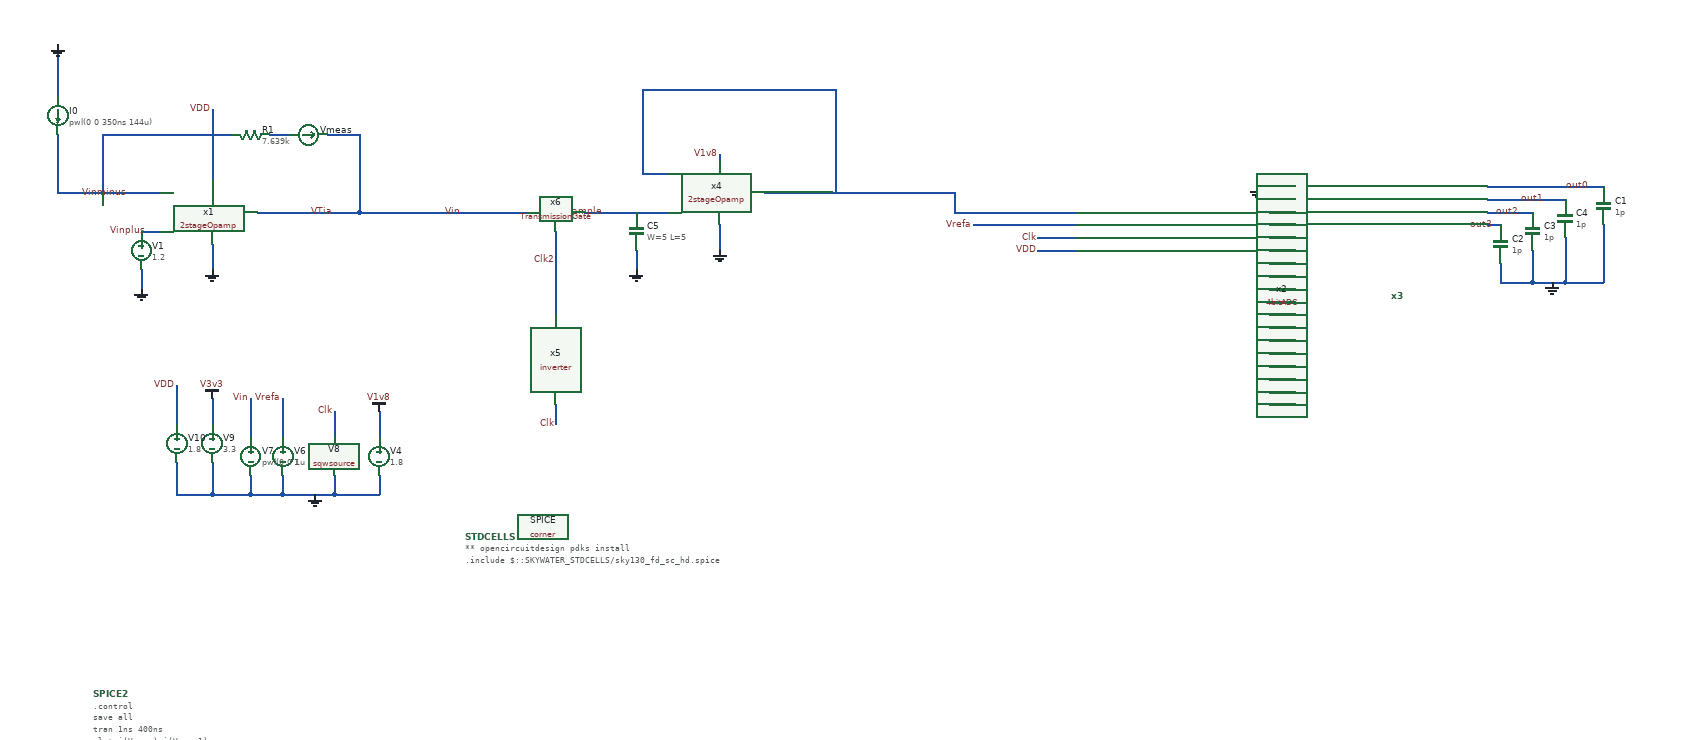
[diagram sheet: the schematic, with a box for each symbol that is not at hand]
v {xschem version=3.4.4 file_version=1.2
}
G {}
K {}
V {}
S {}
E {}
B 2 420 -600 1220 -200 {flags=graph
y1=0
y2=2
ypos1=0.1
ypos2=2.1
divy=1.8
subdivy=1
unity=1
x1=1.93715e-07
x2=4.23938e-07
divx=5
subdivx=1
xlabmag=1.0
ylabmag=1.0
node=BUS_NAME,x3.xoutput19.a_109_47#,x3.xoutput18.a_109_47#,x3.xoutput17.a_109_47#,x3.xoutput16.a_109_47#
color=4
dataset=-1
unitx=1
logx=0
logy=0
digital=1}
N -755 -80 -755 10 {
lab=Vinminus}
N -755 10 -595 10 {
lab=Vinminus}
N -755 -220 -755 -140 {
lab=GND}
N -445 40 -285 40 {
lab=VTia}
N -285 -80 -285 40 {
lab=VTia}
N -685 -80 -485 -80 {
lab=Vinminus}
N -685 -80 -685 10 {
lab=Vinminus}
N -625 130 -625 160 {
lab=GND}
N -425 -80 -395 -80 {
lab=#net1}
N -335 -80 -285 -80 {
lab=VTia}
N -285 40 -195 40 {
lab=VTia}
N 770 100 830 100 {
lab=VDD}
N 770 80 830 80 {
lab=Clk}
N 770 60 830 60 {
lab=Vrefa}
N 1130 40 1170 40 {
lab=#net2}
N 1130 60 1170 60 {
lab=#net3}
N 1130 80 1170 80 {
lab=#net4}
N 1130 100 1170 100 {
lab=#net5}
N 1130 120 1170 120 {
lab=#net6}
N 1130 140 1170 140 {
lab=#net7}
N 1130 160 1170 160 {
lab=#net8}
N 1130 180 1170 180 {
lab=#net9}
N 1130 200 1170 200 {
lab=#net10}
N 1130 220 1170 220 {
lab=#net11}
N 1130 240 1170 240 {
lab=#net12}
N 1130 260 1170 260 {
lab=#net13}
N 1130 280 1170 280 {
lab=#net14}
N 1130 300 1170 300 {
lab=#net15}
N 1130 320 1170 320 {
lab=#net16}
N 1130 340 1170 340 {
lab=#net17}
N 1470 0 1650 0 {
lab=out0}
N 1470 20 1590 20 {
lab=out1}
N 1470 40 1540 40 {
lab=out2}
N 1470 60 1490 60 {
lab=out3}
N 1490 120 1490 150 {
lab=GND}
N 1540 100 1540 150 {
lab=GND}
N 1590 80 1590 150 {
lab=GND}
N 1650 60 1650 150 {
lab=GND}
N 1590 150 1650 150 {
lab=GND}
N 1540 150 1590 150 {
lab=GND}
N 1490 150 1540 150 {
lab=GND}
N 1110 0 1170 0 {
lab=GND}
N 1150 20 1170 20 {
lab=VDD}
N 640 40 830 40 {
lab=#net18}
N 670 60 770 60 {
lab=Vrefa}
N -195 40 -125 40 {
lab=VTia}
N -515 -30 -515 -10 {
lab=VDD}
N -515 90 -515 110 {
lab=GND}
N 640 10 640 40 {
lab=#net18}
N 450 10 640 10 {
lab=#net18}
N -625 70 -595 70 {
lab=Vinplus}
N -515 -120 -515 -30 {
lab=VDD}
N -515 110 -515 130 {
lab=GND}
N -125 40 -25 40 {
lab=VTia}
N 145 100 145 130 {
lab=GND}
N 145 40 195 40 {
lab=Vsample}
N 365 10 455 10 {
lab=#net18}
N 455 -150 455 10 {
lab=#net18}
N 155 -150 455 -150 {
lab=#net18}
N 275 60 275 100 {
lab=GND}
N 155 -20 195 -20 {
lab=#net18}
N 155 -150 155 -20 {
lab=#net18}
N 345 10 365 10 {
lab=#net18}
N 275 -50 275 -40 {
lab=V1v8}
N 20 340 20 370 {
lab=Clk}
N 20 70 20 110 {
lab=Clk2}
N 20 110 20 130 {
lab=Clk2}
N 20 130 20 200 {
lab=Clk2}
N 65 40 95 40 {
lab=Vsample}
N 95 40 145 40 {
lab=Vsample}
N -405 330 -405 390 {
lab=Vrefa}
N -455 330 -455 390 {
lab=Vin}
N -255 350 -255 390 {
lab=V1v8}
N -325 350 -325 390 {
lab=Clk}
N -455 450 -455 480 {
lab=GND}
N -325 480 -255 480 {
lab=GND}
N -255 450 -255 480 {
lab=GND}
N -405 450 -405 480 {
lab=GND}
N -325 450 -325 480 {
lab=GND}
N -455 480 -405 480 {
lab=GND}
N -405 480 -325 480 {
lab=GND}
N -515 330 -515 370 {
lab=V3v3}
N -515 430 -515 460 {
lab=GND}
N -515 460 -515 480 {
lab=GND}
N -515 480 -455 480 {
lab=GND}
N -570 310 -570 370 {
lab=VDD}
N -570 430 -570 460 {
lab=GND}
N -570 460 -570 480 {
lab=GND}
N -570 480 -520 480 {
lab=GND}
N -520 480 -515 480 {
lab=GND}
C {devices/isource.sym} -755 -110 0 0 {name=I0 value="pwl(0 0 350ns 144u)"}
C {devices/gnd.sym} -755 -220 2 0 {name=l1 lab=GND}
C {devices/res.sym} -455 -80 1 0 {name=R1
value=7.639k
footprint=1206
device=resistor
m=1}
C {devices/lab_pin.sym} -325 40 1 0 {name=p1 sig_type=std_logic lab=VTia}
C {devices/lab_pin.sym} -645 10 1 0 {name=p2 sig_type=std_logic lab=Vinminus}
C {devices/vsource.sym} -625 100 0 0 {name=V1 value=1.2 savecurrent=false}
C {devices/gnd.sym} -625 160 0 0 {name=l2 lab=GND}
C {devices/ammeter.sym} -365 -80 3 0 {name=Vmeas savecurrent=true}
C {sky130_fd_pr/corner.sym} 0 530 0 0 {name=SPICE only_toplevel=true corner=tt}
C {devices/launcher.sym} -870 570 0 0 {name=h15
descr="Annotate OP" 
tclcommand="set show_hidden_texts 1; xschem annotate_op"
}
C {devices/launcher.sym} -860 620 0 0 {name=h3
descr="Netlist & sim" 
tclcommand="xschem netlist; xschem simulate"}
C {devices/code_shown.sym} -700 790 0 0 {name=SPICE2
only_toplevel=false 
value="
.control
save all

tran 1ns 400ns
plot i(Vmeas) i(Vmeas1)
plot Vtia Vmeas
plot Vinadc Vtia
plot Clk
plot Vtia Clk
plot out0 out1 out2 out3
plot Vinminus Vinplus
appendwrite
write Tia_ADCtb.raw
.endc
"}
C {devices/lab_pin.sym} 770 80 0 0 {name=p10 lab=Clk}
C {devices/lab_pin.sym} 1150 20 2 1 {name=p11 sig_type=std_logic lab=VDD}
C {devices/code.sym} -120 545 0 0 {name=STDCELLS
only_toplevel=true
format="tcleval( @value )"
value="
** opencircuitdesign pdks install
.include $::SKYWATER_STDCELLS/sky130_fd_sc_hd.spice

"
spice_ignore=false}
C {devices/lab_pin.sym} 770 100 2 1 {name=p12 sig_type=std_logic lab=VDD}
C {devices/gnd.sym} 1110 0 1 0 {name=l4 lab=GND}
C {devices/capa.sym} 1650 30 0 0 {name=C1
m=1
value=1p
footprint=1206
device="ceramic capacitor"}
C {devices/capa.sym} 1490 90 0 0 {name=C2
m=1
value=1p
footprint=1206
device="ceramic capacitor"}
C {devices/capa.sym} 1540 70 0 0 {name=C3
m=1
value=1p
footprint=1206
device="ceramic capacitor"}
C {devices/capa.sym} 1590 50 0 0 {name=C4
m=1
value=1p
footprint=1206
device="ceramic capacitor"}
C {devices/gnd.sym} 1570 150 0 0 {name=l5 lab=GND}
C {devices/lab_pin.sym} 1630 0 1 0 {name=p13 sig_type=std_logic lab=out0}
C {devices/lab_pin.sym} 1560 20 1 0 {name=p14 sig_type=std_logic lab=out1}
C {devices/lab_pin.sym} 1520 40 1 0 {name=p15 sig_type=std_logic lab=out2}
C {devices/lab_pin.sym} 1480 60 1 0 {name=p16 sig_type=std_logic lab=out3}
C {devices/lab_pin.sym} 670 60 0 0 {name=p5 sig_type=std_logic lab=Vrefa}
C {devices/lab_pin.sym} -615 70 1 0 {name=p4 sig_type=std_logic lab=Vinplus}
C {devices/gnd.sym} -515 130 0 0 {name=l6 lab=GND}
C {devices/lab_pin.sym} -515 -120 1 0 {name=p6 sig_type=std_logic lab=VDD}
C {devices/launcher.sym} 800 -130 0 0 {name=h5
descr="load waves" 
tclcommand="xschem raw_read $netlist_dir/Tia_ADCtb.raw tran"
}
C {xschem/Amplifiers/2stageOpamp.sym} -525 50 0 0 {name=x1}
C {xschem/DataConverters/4bitADC.sym} 980 350 0 0 {name=x2}
C {xschem/StandardCells/Priority_Encoder_16t4.sym} 1320 170 0 0 {name=x3 prefix=sky130_fd_sc_hd__ }
C {devices/lab_pin.sym} -125 40 0 0 {name=p7 lab=Vin
}
C {devices/lab_pin.sym} 20 370 3 0 {name=p8 lab=Clk}
C {devices/gnd.sym} 145 130 0 1 {name=l7 lab=GND}
C {devices/lab_pin.sym} 275 -50 3 1 {name=p9 sig_type=std_logic lab=V1v8}
C {devices/gnd.sym} 275 100 0 1 {name=l8 lab=GND}
C {devices/lab_pin.sym} 95 40 1 0 {name=p19 sig_type=std_logic lab=Vsample}
C {devices/lab_pin.sym} 20 115 0 0 {name=p20 sig_type=std_logic lab=Clk2}
C {dependencies/pdks/sky130B/libs.tech/xschem/sky130_fd_pr/cap_mim_m3_2.sym} 145 70 0 0 {name=C5 model=cap_mim_m3_2 W=5 L=5 MF=10 spiceprefix=X}
C {xschem/StandardCells/TransmissionGate.sym} -35 40 2 0 {name=x6}
C {xschem/Amplifiers/2stageOpamp.sym} 265 20 0 0 {name=x4}
C {xschem/StandardCells/inverter.sym} 20 280 3 0 {name=x5}
C {devices/lab_pin.sym} -325 350 1 0 {name=p17 lab=Clk}
C {devices/vsource.sym} -255 420 0 0 {name=V4 value=1.8 savecurrent=false}
C {devices/vsource.sym} -405 420 0 0 {name=V6 value=1 savecurrent=true
}
C {devices/lab_pin.sym} -405 330 1 0 {name=p18 sig_type=std_logic lab=Vrefa}
C {devices/vsource.sym} -455 420 0 0 {name=V7 value="pwl(0 0 1u 1.1)" savecurrent=true}
C {devices/gnd.sym} -355 480 0 1 {name=l10 lab=GND}
C {devices/sqwsource.sym} -325 420 0 0 {name=V8 vhi=1.8 freq=60e6}
C {devices/vsource.sym} -515 400 0 0 {name=V9 value=3.3 savecurrent=false}
C {devices/vsource.sym} -570 400 0 0 {name=V10 value=1.8 savecurrent=true}
C {devices/lab_pin.sym} -570 310 1 0 {name=p21 lab=VDD
}
C {devices/lab_pin.sym} -455 330 1 0 {name=p22 sig_type=std_logic lab=Vin}
C {devices/vdd.sym} -255 350 0 0 {name=l9 lab=V1v8}
C {devices/vdd.sym} -515 330 0 0 {name=l11 lab=V3v3}
